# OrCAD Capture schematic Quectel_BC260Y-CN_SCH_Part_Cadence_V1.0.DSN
size A1

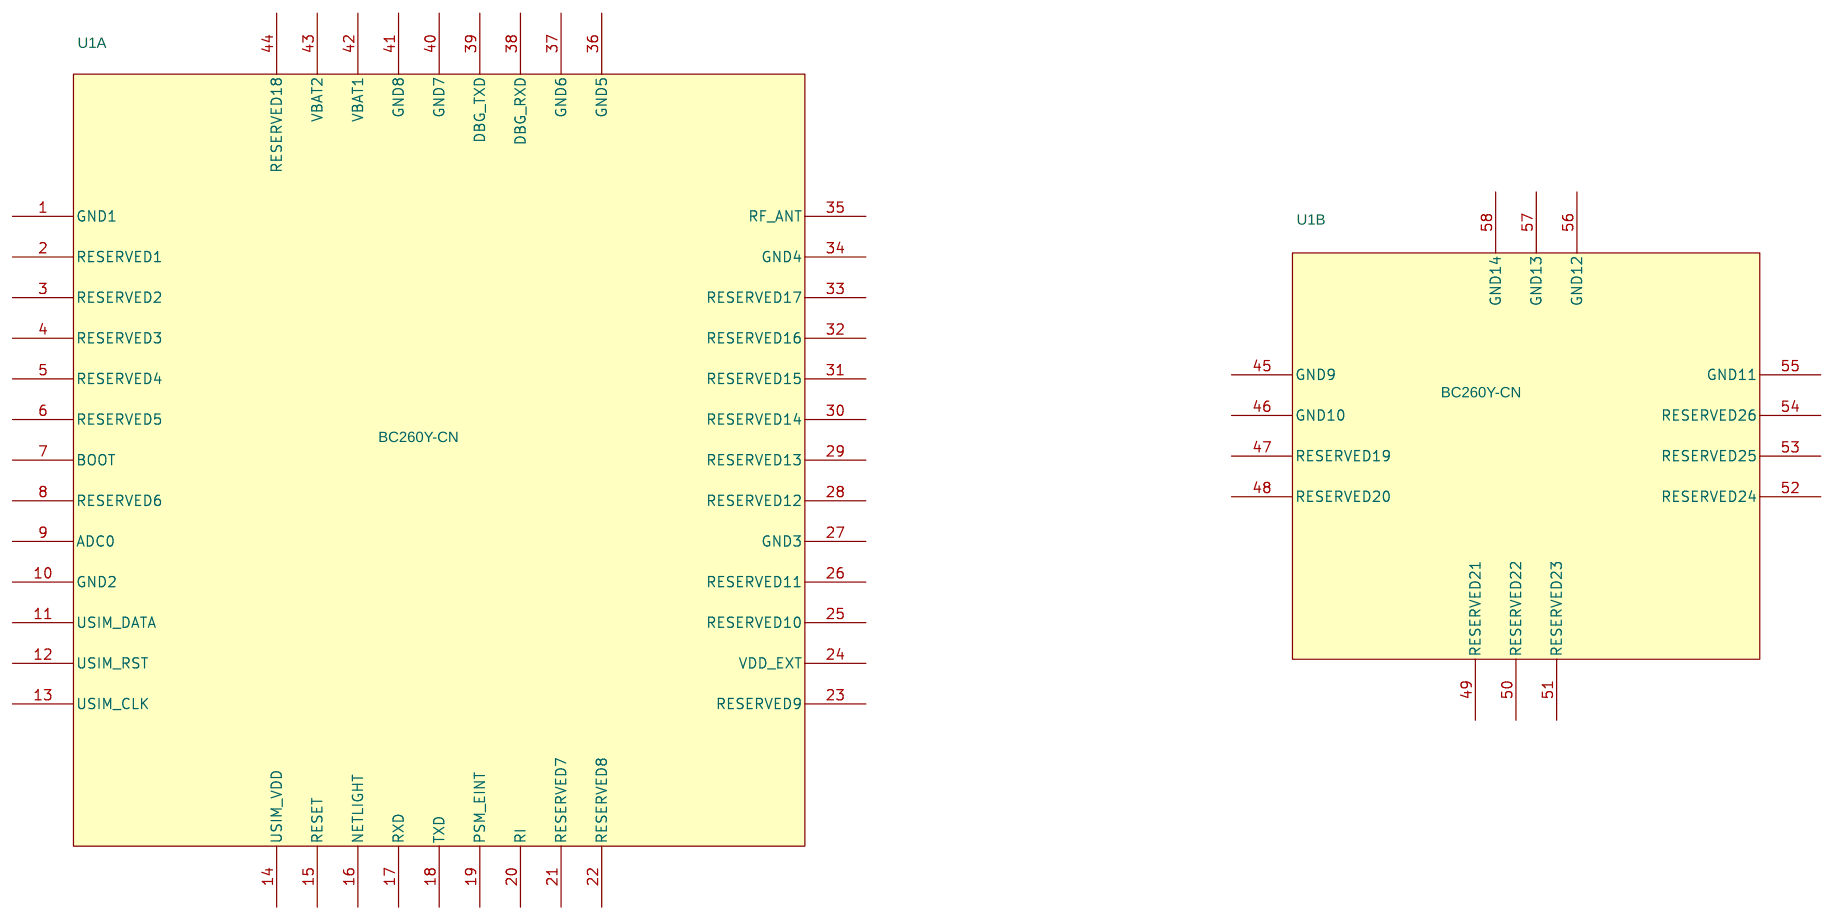
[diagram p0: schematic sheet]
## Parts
U1  BC260Y-CN  (sections A,B)

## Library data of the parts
U1 = BC260Y-CN

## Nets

Not connected (* = marked no-connect by the designer): U1 1(GND1) 2(RESERVED1) 3(RESERVED2) 4(RESERVED3) 5(RESERVED4) 6(RESERVED5) 7(BOOT) 8(RESERVED6) 9(ADC0) 10(GND2) 11(USIM_DATA) 12(USIM_RST) 13(USIM_CLK) 14(USIM_VDD) 15(RESET) 16(NETLIGHT) 17(RXD) 18(TXD) 19(PSM_EINT) 20(RI) 21(RESERVED7) 22(RESERVED8) 23(RESERVED9) 24(VDD_EXT) 25(RESERVED10) 26(RESERVED11) 27(GND3) 28(RESERVED12) 29(RESERVED13) 30(RESERVED14) 31(RESERVED15) 32(RESERVED16) 33(RESERVED17) 34(GND4) 35(RF_ANT) 36(GND5) 37(GND6) 38(DBG_RXD) 39(DBG_TXD) 40(GND7) 41(GND8) 42(VBAT1) 43(VBAT2) 44(RESERVED18) 45(GND9) 46(GND10) 47(RESERVED19) 48(RESERVED20) 49(RESERVED21) 50(RESERVED22) 51(RESERVED23) 52(RESERVED24) 53(RESERVED25) 54(RESERVED26) 55(GND11) 56(GND12) 57(GND13) 58(GND14)
